VERSION 5.7 ;
  NOWIREEXTENSIONATPIN ON ;
  DIVIDERCHAR "/" ;
  BUSBITCHARS "[]" ;
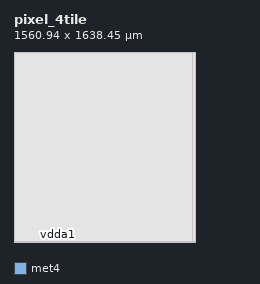
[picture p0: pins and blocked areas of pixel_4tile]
MACRO pixel_4tile
  CLASS BLOCK ;
  FOREIGN pixel_4tile ;
  ORIGIN 0.940 0.005 ;
  SIZE 1560.940 BY 1638.450 ;
  PIN vdda1
    ANTENNADIFFAREA 37974.839844 ;
    PORT
      LAYER met4 ;
        RECT 368.795 50.390 380.585 52.050 ;
    END
  END vdda1
  OBS
      LAYER nwell ;
        RECT -0.940 -0.005 1542.320 1638.445 ;
      LAYER li1 ;
        RECT -0.605 0.125 1541.985 1638.315 ;
      LAYER met1 ;
        RECT -0.665 0.065 1542.950 1638.375 ;
      LAYER met2 ;
        RECT 0.765 0.295 1560.000 1638.230 ;
      LAYER met3 ;
        RECT 0.765 0.125 1560.000 1638.315 ;
      LAYER met4 ;
        RECT 1.565 52.450 1539.815 1638.290 ;
        RECT 1.565 49.990 368.395 52.450 ;
        RECT 380.985 49.990 1539.815 52.450 ;
        RECT 1.565 0.150 1539.815 49.990 ;
      LAYER met5 ;
        RECT 0.000 0.475 1541.380 1637.965 ;
  END
END pixel_4tile
END LIBRARY

